VERSION 5.7 ;
  NOWIREEXTENSIONATPIN ON ;
  DIVIDERCHAR "/" ;
  BUSBITCHARS "[]" ;
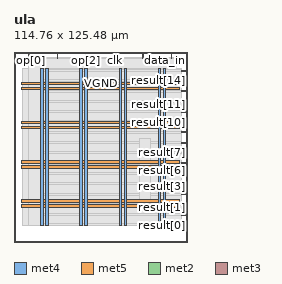
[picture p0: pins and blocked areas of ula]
MACRO ula
  CLASS BLOCK ;
  FOREIGN ula ;
  ORIGIN 0.000 0.000 ;
  SIZE 114.760 BY 125.480 ;
  PIN VGND
    DIRECTION INOUT ;
    USE GROUND ;
    PORT
      LAYER met4 ;
        RECT 20.955 10.640 22.555 114.480 ;
    END
    PORT
      LAYER met4 ;
        RECT 46.830 10.640 48.430 114.480 ;
    END
    PORT
      LAYER met4 ;
        RECT 72.705 10.640 74.305 114.480 ;
    END
    PORT
      LAYER met4 ;
        RECT 98.580 10.640 100.180 114.480 ;
    END
    PORT
      LAYER met5 ;
        RECT 5.280 26.300 109.260 27.900 ;
    END
    PORT
      LAYER met5 ;
        RECT 5.280 52.140 109.260 53.740 ;
    END
    PORT
      LAYER met5 ;
        RECT 5.280 77.980 109.260 79.580 ;
    END
    PORT
      LAYER met5 ;
        RECT 5.280 103.820 109.260 105.420 ;
    END
  END VGND
  PIN VPWR
    DIRECTION INOUT ;
    USE POWER ;
    PORT
      LAYER met4 ;
        RECT 17.655 10.640 19.255 114.480 ;
    END
    PORT
      LAYER met4 ;
        RECT 43.530 10.640 45.130 114.480 ;
    END
    PORT
      LAYER met4 ;
        RECT 69.405 10.640 71.005 114.480 ;
    END
    PORT
      LAYER met4 ;
        RECT 95.280 10.640 96.880 114.480 ;
    END
    PORT
      LAYER met5 ;
        RECT 5.280 23.000 109.260 24.600 ;
    END
    PORT
      LAYER met5 ;
        RECT 5.280 48.840 109.260 50.440 ;
    END
    PORT
      LAYER met5 ;
        RECT 5.280 74.680 109.260 76.280 ;
    END
    PORT
      LAYER met5 ;
        RECT 5.280 100.520 109.260 102.120 ;
    END
  END VPWR
  PIN clk
    DIRECTION INPUT ;
    USE SIGNAL ;
    ANTENNAGATEAREA 0.852000 ;
    PORT
      LAYER met2 ;
        RECT 66.330 121.480 66.610 125.480 ;
    END
  END clk
  PIN data_in
    DIRECTION INPUT ;
    USE SIGNAL ;
    ANTENNAGATEAREA 0.196500 ;
    PORT
      LAYER met2 ;
        RECT 104.050 121.480 104.330 125.480 ;
    END
  END data_in
  PIN en_in
    DIRECTION INPUT ;
    USE SIGNAL ;
    ANTENNAGATEAREA 0.213000 ;
    PORT
      LAYER met2 ;
        RECT 85.190 121.480 85.470 125.480 ;
    END
  END en_in
  PIN op[0]
    DIRECTION INPUT ;
    USE SIGNAL ;
    ANTENNAGATEAREA 0.247500 ;
    PORT
      LAYER met2 ;
        RECT 9.750 121.480 10.030 125.480 ;
    END
  END op[0]
  PIN op[1]
    DIRECTION INPUT ;
    USE SIGNAL ;
    ANTENNAGATEAREA 0.247500 ;
    PORT
      LAYER met2 ;
        RECT 28.610 121.480 28.890 125.480 ;
    END
  END op[1]
  PIN op[2]
    DIRECTION INPUT ;
    USE SIGNAL ;
    ANTENNAGATEAREA 0.213000 ;
    PORT
      LAYER met2 ;
        RECT 47.470 121.480 47.750 125.480 ;
    END
  END op[2]
  PIN result[0]
    DIRECTION OUTPUT TRISTATE ;
    USE SIGNAL ;
    ANTENNADIFFAREA 0.445500 ;
    PORT
      LAYER met3 ;
        RECT 110.760 10.920 114.760 11.520 ;
    END
  END result[0]
  PIN result[10]
    DIRECTION OUTPUT TRISTATE ;
    USE SIGNAL ;
    ANTENNADIFFAREA 0.445500 ;
    PORT
      LAYER met3 ;
        RECT 110.760 78.920 114.760 79.520 ;
    END
  END result[10]
  PIN result[11]
    DIRECTION OUTPUT TRISTATE ;
    USE SIGNAL ;
    ANTENNADIFFAREA 0.445500 ;
    PORT
      LAYER met3 ;
        RECT 110.760 85.720 114.760 86.320 ;
    END
  END result[11]
  PIN result[12]
    DIRECTION OUTPUT TRISTATE ;
    USE SIGNAL ;
    ANTENNADIFFAREA 0.445500 ;
    PORT
      LAYER met3 ;
        RECT 110.760 92.520 114.760 93.120 ;
    END
  END result[12]
  PIN result[13]
    DIRECTION OUTPUT TRISTATE ;
    USE SIGNAL ;
    ANTENNADIFFAREA 0.445500 ;
    PORT
      LAYER met3 ;
        RECT 110.760 99.320 114.760 99.920 ;
    END
  END result[13]
  PIN result[14]
    DIRECTION OUTPUT TRISTATE ;
    USE SIGNAL ;
    ANTENNADIFFAREA 0.795200 ;
    PORT
      LAYER met3 ;
        RECT 110.760 106.120 114.760 106.720 ;
    END
  END result[14]
  PIN result[15]
    DIRECTION OUTPUT TRISTATE ;
    USE SIGNAL ;
    ANTENNADIFFAREA 0.795200 ;
    PORT
      LAYER met3 ;
        RECT 110.760 112.920 114.760 113.520 ;
    END
  END result[15]
  PIN result[1]
    DIRECTION OUTPUT TRISTATE ;
    USE SIGNAL ;
    ANTENNADIFFAREA 0.445500 ;
    PORT
      LAYER met3 ;
        RECT 110.760 17.720 114.760 18.320 ;
    END
  END result[1]
  PIN result[2]
    DIRECTION OUTPUT TRISTATE ;
    USE SIGNAL ;
    ANTENNADIFFAREA 0.445500 ;
    PORT
      LAYER met3 ;
        RECT 110.760 24.520 114.760 25.120 ;
    END
  END result[2]
  PIN result[3]
    DIRECTION OUTPUT TRISTATE ;
    USE SIGNAL ;
    ANTENNADIFFAREA 0.795200 ;
    PORT
      LAYER met3 ;
        RECT 110.760 31.320 114.760 31.920 ;
    END
  END result[3]
  PIN result[4]
    DIRECTION OUTPUT TRISTATE ;
    USE SIGNAL ;
    ANTENNADIFFAREA 0.795200 ;
    PORT
      LAYER met3 ;
        RECT 110.760 38.120 114.760 38.720 ;
    END
  END result[4]
  PIN result[5]
    DIRECTION OUTPUT TRISTATE ;
    USE SIGNAL ;
    ANTENNADIFFAREA 0.445500 ;
    PORT
      LAYER met3 ;
        RECT 110.760 44.920 114.760 45.520 ;
    END
  END result[5]
  PIN result[6]
    DIRECTION OUTPUT TRISTATE ;
    USE SIGNAL ;
    ANTENNADIFFAREA 0.445500 ;
    PORT
      LAYER met3 ;
        RECT 110.760 51.720 114.760 52.320 ;
    END
  END result[6]
  PIN result[7]
    DIRECTION OUTPUT TRISTATE ;
    USE SIGNAL ;
    ANTENNADIFFAREA 0.445500 ;
    PORT
      LAYER met3 ;
        RECT 110.760 58.520 114.760 59.120 ;
    END
  END result[7]
  PIN result[8]
    DIRECTION OUTPUT TRISTATE ;
    USE SIGNAL ;
    ANTENNADIFFAREA 0.445500 ;
    PORT
      LAYER met3 ;
        RECT 110.760 65.320 114.760 65.920 ;
    END
  END result[8]
  PIN result[9]
    DIRECTION OUTPUT TRISTATE ;
    USE SIGNAL ;
    ANTENNADIFFAREA 0.445500 ;
    PORT
      LAYER met3 ;
        RECT 110.760 72.120 114.760 72.720 ;
    END
  END result[9]
  OBS
      LAYER li1 ;
        RECT 5.520 10.795 109.020 114.325 ;
      LAYER met1 ;
        RECT 5.520 10.640 109.320 114.480 ;
      LAYER met2 ;
        RECT 10.310 121.200 28.330 122.130 ;
        RECT 29.170 121.200 47.190 122.130 ;
        RECT 48.030 121.200 66.050 122.130 ;
        RECT 66.890 121.200 84.910 122.130 ;
        RECT 85.750 121.200 103.770 122.130 ;
        RECT 104.610 121.200 107.540 122.130 ;
        RECT 9.760 10.695 107.540 121.200 ;
      LAYER met3 ;
        RECT 17.665 113.920 110.760 114.405 ;
        RECT 17.665 112.520 110.360 113.920 ;
        RECT 17.665 107.120 110.760 112.520 ;
        RECT 17.665 105.720 110.360 107.120 ;
        RECT 17.665 100.320 110.760 105.720 ;
        RECT 17.665 98.920 110.360 100.320 ;
        RECT 17.665 93.520 110.760 98.920 ;
        RECT 17.665 92.120 110.360 93.520 ;
        RECT 17.665 86.720 110.760 92.120 ;
        RECT 17.665 85.320 110.360 86.720 ;
        RECT 17.665 79.920 110.760 85.320 ;
        RECT 17.665 78.520 110.360 79.920 ;
        RECT 17.665 73.120 110.760 78.520 ;
        RECT 17.665 71.720 110.360 73.120 ;
        RECT 17.665 66.320 110.760 71.720 ;
        RECT 17.665 64.920 110.360 66.320 ;
        RECT 17.665 59.520 110.760 64.920 ;
        RECT 17.665 58.120 110.360 59.520 ;
        RECT 17.665 52.720 110.760 58.120 ;
        RECT 17.665 51.320 110.360 52.720 ;
        RECT 17.665 45.920 110.760 51.320 ;
        RECT 17.665 44.520 110.360 45.920 ;
        RECT 17.665 39.120 110.760 44.520 ;
        RECT 17.665 37.720 110.360 39.120 ;
        RECT 17.665 32.320 110.760 37.720 ;
        RECT 17.665 30.920 110.360 32.320 ;
        RECT 17.665 25.520 110.760 30.920 ;
        RECT 17.665 24.120 110.360 25.520 ;
        RECT 17.665 18.720 110.760 24.120 ;
        RECT 17.665 17.320 110.360 18.720 ;
        RECT 17.665 11.920 110.760 17.320 ;
        RECT 17.665 10.715 110.360 11.920 ;
      LAYER met4 ;
        RECT 83.095 27.375 89.865 68.505 ;
  END
END ula
END LIBRARY

